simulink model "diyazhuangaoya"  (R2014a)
settings: Solver=ode45  SolverMode=SingleTasking  StartTime=0.0  StopTime=0.025  RelTol=1e-3
undefined symbols (not defined in the file): xiezhendiangan
libraries: powerlib x32, powerlib_meascontrol x8, simulink x4

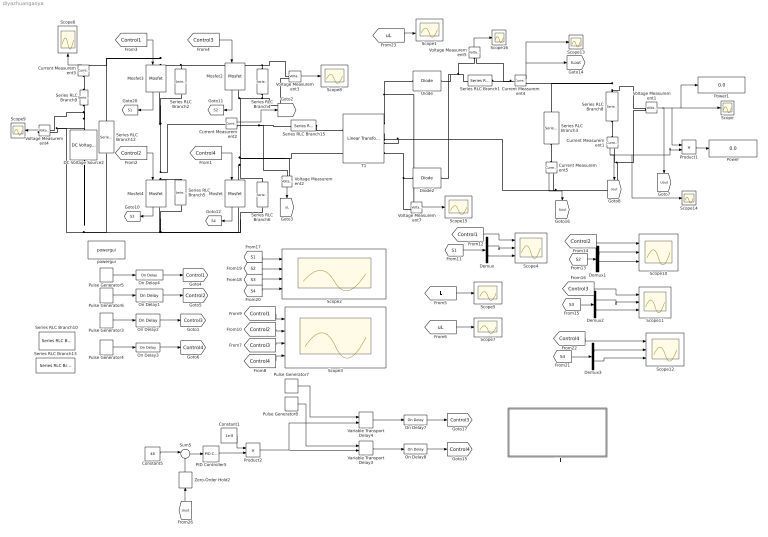
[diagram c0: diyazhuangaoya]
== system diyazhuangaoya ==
  Constant1 : Constant  Value=1e-8
  Constant5 : Constant  Value=48
  Current Measurement{1..5} (5 alike) : powerlib/Measurements/Current Measurement  PhasorSimulation=off  OutputType=Complex  PSBequivalent=0
  DC Voltage Source2 : powerlib/Electrical Sources/DC Voltage Source  Amplitude=28  Measurements=None
  Demux{,1..3} (4 alike) : Demux  Outputs=2
  Diode : powerlib/Power Electronics/Diode  Ron=0.001  Lon=0  Vf=0.8  IC=0  UseSnubber=0  Rs=500  Cs=250e-9  Measurements=off
  Diode2 : powerlib/Power Electronics/Diode  Ron=0.001  Lon=0  Vf=0.8  IC=0  UseSnubber=0  Rs=500  Cs=250e-9  Measurements=off
  Mosfet{,2..4} (4 alike) : powerlib/Power Electronics/Mosfet  Ron=3.5e-3  Lon=0  Rd=0.01  Vfd=0.7  IC=0  Rs=1e5  Cs=inf  Measurements=on
  On Delay1 : powerlib_meascontrol/Logic/On Delay  DelayType=On delay  delay=120e-9  ic=0  Ts=0
  On Delay2 : powerlib_meascontrol/Logic/On Delay  Commented=on  DelayType=On delay  delay=120e-9  ic=0  Ts=0
  On Delay3 : powerlib_meascontrol/Logic/On Delay  Commented=on  DelayType=On delay  delay=120e-9  ic=0  Ts=0
  On Delay4 : powerlib_meascontrol/Logic/On Delay  DelayType=On delay  delay=120e-9  ic=0  Ts=0
  On Delay7 : powerlib_meascontrol/Logic/On Delay  DelayType=On delay  delay=1.2e-7  ic=0  Ts=0
  On Delay8 : powerlib_meascontrol/Logic/On Delay  DelayType=On delay  delay=1.2e-7  ic=0  Ts=0
  PID Controller5 : simulink/Continuous/PID Controller  Controller=PID  TimeDomain=Continuous-time  SampleTime=-1  IntegratorMethod=Forward Euler  FilterMethod=Forward Euler  Form=Parallel  UseFilter=on  ControllerParametersSource=internal  P=0.05  I=1  D=0  N=100  InitialConditionSource=internal  InitialConditionForIntegrator=0  InitialConditionForFilter=0  ExternalReset=none  LimitOutput=off  UpperSaturationLimit=inf  LowerSaturationLimit=-inf  LinearizeAsGain=on  AntiWindupMode=none  Kb=1  TrackingMode=off  Kt=1  PParamMin=[]  PParamMax=[]  IParamMin=[]  IParamMax=[]  DParamMin=[]  DParamMax=[]  NParamMin=[]  NParamMax=[]  KbParamMin=[]  KbParamMax=[]  KtParamMin=[]  KtParamMax=[]  POutMin=[]  POutMax=[]  IOutMin=[]  IOutMax=[]  DOutMin=[]  DOutMax=[]  NOutMin=[]  NOutMax=[]  KbOutMin=[]  KbOutMax=[]  KtOutMin=[]  KtOutMax=[]  IntegratorOutMin=[]  IntegratorOutMax=[]  FilterOutMin=[]  FilterOutMax=[]  SumOutMin=[]  SumOutMax=[]  SumI1OutMin=[]  SumI1OutMax=[]  SumI2OutMin=[]  SumI2OutMax=[]  SumI3OutMin=[]  SumI3OutMax=[]  SumDOutMin=[]  SumDOutMax=[]  SaturationOutMin=[]  SaturationOutMax=[]  IntegratorContinuousStateAttributes=''  IntegratorStateMustResolveToSignalObject=off  IntegratorRTWStateStorageClass=Auto  FilterContinuousStateAttributes=''  FilterStateMustResolveToSignalObject=off  FilterRTWStateStorageClass=Auto  DifferentiatorICPrevScaledInput=0  DifferentiatorOutMin=[]  DifferentiatorOutMax=[]
  Power : Display
  Power1 : Display
  Product1 : Product
  Product2 : Product
  Pulse Generator3 : DiscretePulseGenerator  Commented=on  PulseType=Time based  Period=0.00001  PulseWidth=50  PhaseDelay=0.5*0.00001
  Pulse Generator4 : DiscretePulseGenerator  Commented=on  PulseType=Time based  Period=0.00001  PulseWidth=50  PhaseDelay=0.00001/2+0.5*0.00001
  Pulse Generator5 : DiscretePulseGenerator  PulseType=Time based  Period=0.00001  PulseWidth=50
  Pulse Generator6 : DiscretePulseGenerator  PulseType=Time based  Period=0.00001  PulseWidth=50  PhaseDelay=0.00001/2
  Pulse Generator7 : DiscretePulseGenerator  PulseType=Time based  Period=0.00001  PulseWidth=50  PhaseDelay=0.5*0.00001
  Pulse Generator8 : DiscretePulseGenerator  PulseType=Time based  Period=0.00001  PulseWidth=50  PhaseDelay=0.00001/2+0.5*0.00001
  Scope{,5..9,13..16} (10 alike) : Scope
  Scope1 : Scope  NumInputPorts=2
  Scope{4,10..12} (4 alike) : Scope  NumInputPorts=3
  Scope2 : Scope  NumInputPorts=4
  Scope3 : Scope  NumInputPorts=4
  Series RLC Branch1 : powerlib/Elements/Series RLC Branch  LConnTagsString=__new0  RConnTagsString=__new0  BranchType=RL  Resistance=0.0001  Inductance=100e-6  SetiL0=off  InitialCurrent=0  Capacitance=1e-6  Setx0=off  InitialVoltage=0  Measurements=None
  Series RLC Branch10 : powerlib/Elements/Series RLC Branch  LConnTagsString=__new0  RConnTagsString=__new0  BranchType=C  Resistance=0.0001  Inductance=2e-3  SetiL0=off  InitialCurrent=0  Capacitance=0.249e-6  Setx0=off  InitialVoltage=0  Measurements=None
  Series RLC Branch12 : powerlib/Elements/Series RLC Branch  LConnTagsString=__new0  RConnTagsString=__new0  BranchType=RC  Resistance=0.01  Inductance=2e-3  SetiL0=off  InitialCurrent=0  Capacitance=30000e-6  Setx0=off  InitialVoltage=0  Measurements=None
  Series RLC Branch13 : powerlib/Elements/Series RLC Branch  LConnTagsString=__new0  RConnTagsString=__new0  BranchType=RL  Resistance=0.0001  Inductance=10e-6  SetiL0=off  InitialCurrent=0  Capacitance=1e-6  Setx0=off  InitialVoltage=0  Measurements=None
  Series RLC Branch15 : powerlib/Elements/Series RLC Branch  LConnTagsString=__new0  RConnTagsString=__new0  BranchType=RL  Resistance=0.0001  Inductance=10e-6  SetiL0=off  InitialCurrent=0  Capacitance=1e-6  Setx0=off  InitialVoltage=0  Measurements=None
  Series RLC Branch2 : powerlib/Elements/Series RLC Branch  LConnTagsString=__new0  RConnTagsString=__new0  BranchType=C  Resistance=1  Inductance=xiezhendiangan  SetiL0=off  InitialCurrent=0  Capacitance=1020*10e-12  Setx0=off  InitialVoltage=0  Measurements=None
  Series RLC Branch3 : powerlib/Elements/Series RLC Branch  LConnTagsString=__new0  RConnTagsString=__new0  BranchType=RC  Resistance=0.01  Inductance=2e-3  SetiL0=off  InitialCurrent=0  Capacitance=200e-6  Setx0=off  InitialVoltage=0  Measurements=None
  Series RLC Branch4 : powerlib/Elements/Series RLC Branch  LConnTagsString=__new0  RConnTagsString=__new0  BranchType=C  Resistance=1  Inductance=xiezhendiangan  SetiL0=off  InitialCurrent=0  Capacitance=10e-12  Setx0=off  InitialVoltage=0  Measurements=None
  Series RLC Branch5 : powerlib/Elements/Series RLC Branch  LConnTagsString=__new0  RConnTagsString=__new0  BranchType=C  Resistance=1  Inductance=xiezhendiangan  SetiL0=off  InitialCurrent=0  Capacitance=10e-12  Setx0=off  InitialVoltage=0  Measurements=None
  Series RLC Branch6 : powerlib/Elements/Series RLC Branch  LConnTagsString=__new0  RConnTagsString=__new0  BranchType=C  Resistance=1  Inductance=xiezhendiangan  SetiL0=off  InitialCurrent=0  Capacitance=10e-12  Setx0=off  InitialVoltage=0  Measurements=None
  Series RLC Branch8 : powerlib/Elements/Series RLC Branch  LConnTagsString=__new0  RConnTagsString=__new0  BranchType=R  Resistance=1.152  Inductance=2e-3  SetiL0=off  InitialCurrent=0  Capacitance=1e-6  Setx0=off  InitialVoltage=0  Measurements=None
  Series RLC Branch9 : powerlib/Elements/Series RLC Branch  LConnTagsString=__new0  RConnTagsString=__new0  BranchType=R  Resistance=1e-2  Inductance=2e-3  SetiL0=off  InitialCurrent=0  Capacitance=1e-6  Setx0=off  InitialVoltage=0  Measurements=None
  Sum5 : Sum  Inputs=|+-
  T1 : powerlib/Elements/Linear Transformer  UNITS=SI  NominalPower=[4000 10e4]  winding1=[2 0 0]  winding2=[6 0 0]  ThreeWindings=on  winding3=[6 0 0]  RmLm=[9e+06 Inf]  Measurements=None  DataType=on
  Variable Transport Delay3 : VariableTransportDelay  VariableDelayType=Variable transport delay  MaximumDelay=0.00001*0.5  MaximumPoints=5120
  Variable Transport Delay4 : VariableTransportDelay  VariableDelayType=Variable transport delay  MaximumDelay=0.00001*0.5  MaximumPoints=5120
  Voltage Measurement{1..5,7} (6 alike) : powerlib/Measurements/Voltage Measurement  PhasorSimulation=off  OutputType=Complex  PSBequivalent=0
  Zero-Order Hold2 : ZeroOrderHold  SampleTime=1e-6
  powergui : powerlib/powergui  Priority=1  SimulationMode=Discrete  SampleTime=5e-8  frequency=60  Iterations=50  frequencyindice=0  Pbase=100e6  ErrMax=1e-4  UnitsV=kV  UnitsW=MW  buscounter=0  FunctionMessages=off  echomessages=off  EnableUseOfTLC=off  CurrentSourceSwitches=off  DisableSnubberDevices=off  DisableRonSwitches=off  DisableVfSwitches=off  DisplayEquations=off  SolverType=Tustin/Backward Euler (TBE)  Interpol=off  ExternalGateDelay=off  methode=off  Ts=100  x0status=blocks  SPID=on  SwTol=0  HookPort=off  RestoreLinks=warning  ResistiveCurrentMeasurement=off  Frange=[0:2:500]  Ylog=off  Xlog=on  ShowGrid=off  save=off  variable=ZData  structure=0  ZoomFFT=off  StartTime=0.0  cycles=1  DisplayStyle=1  fundamental=60  FreqAxis=off  MaxFrequency=1000  frequencyindicesteady=1  RmsSteady=1  display=off
  双闭环 : Subsystem  Commented=on
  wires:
  Demux1/2 -> Scope10/3
  [Control1] -> Mosfet3/1
  Product1/1 -> Power/1
  [Control4] -> Mosfet/1
  Voltage Measurement4/1 -> Scope9/1
  Product2/1 -> Variable Transport Delay4/2, Variable Transport Delay3/2
  [S2] -> Scope2/2
  [Uout] -> Zero-Order Hold2/1
  Voltage Measurement5/1 -> Scope16/1
  Constant5/1 -> Sum5/1
  Pulse Generator6/1 -> On Delay1/1
  [S4] -> Scope2/4
  Voltage Measurement1/1 -> [Uout], Power1/1, Scope/1, Product1/1
  [S2] -> Demux1/1
  Pulse Generator8/1 -> Variable Transport Delay3/1
  [Control2] -> Scope10/1
  On Delay8/1 -> [Control4]
  [uL] -> Scope7/1
  Sum5/1 -> PID Controller5/1
  On Delay1/1 -> [Control2]
  Variable Transport Delay3/1 -> On Delay8/1
  [S3] -> Demux2/1
  On Delay2/1 -> [Control3]
  Demux1/1 -> Scope10/2
  Demux2/1 -> Scope11/2
  Voltage Measurement7/1 -> Scope15/1
  On Delay7/1 -> [Control3]
  Pulse Generator4/1 -> On Delay3/1
  Variable Transport Delay4/1 -> On Delay7/1
  Current Measurement1/1 -> Product1/2, Scope14/1, [Iout]
  [Control3] -> Mosfet2/1
  Constant1/1 -> Product2/1
  Demux2/2 -> Scope11/3
  Pulse Generator7/1 -> Variable Transport Delay4/1
  Pulse Generator3/1 -> On Delay2/1
  Current Measurement5/1 -> [ILout]
  Current Measurement2/1 -> [iL]
  [S4] -> Demux3/1
  [Control2] -> Mosfet4/1
  On Delay3/1 -> [Control4]
  PID Controller5/1 -> Product2/2
  Demux3/2 -> Scope12/3
  [uL] -> Scope1/2
  [Control1] -> Scope3/1
  Pulse Generator5/1 -> On Delay4/1
  On Delay4/1 -> [Control1]
  Current Measurement3/1 -> Scope6/1
  [Control2] -> Scope3/2
  Demux/2 -> Scope4/3
  Mosfet4/1 -> [S3]
  [S1] -> Demux/1
  Voltage Measurement3/1 -> Scope8/1
  Mosfet3/1 -> [S1]
  Mosfet/1 -> [S4]
  [Control3] -> Scope3/3
  Demux3/1 -> Scope12/2
  [Control4] -> Scope12/1
  Current Measurement4/1 -> [ILout], Scope13/1
  [iL] -> Scope5/1
  [Control1] -> Scope4/1
  [Control4] -> Scope3/4
  [S3] -> Scope2/3
  [S1] -> Scope2/1
  Voltage Measurement2/1 -> [uL]
  Mosfet2/1 -> [S2]
  Demux/1 -> Scope4/2
  [Control3] -> Scope11/1
  Zero-Order Hold2/1 -> Sum5/2
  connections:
  Series RLC Branch4/RConn1 -- Series RLC Branch12/LConn1 -- Current Measurement3/RConn1 -- Mosfet3/LConn1 -- Series RLC Branch2/RConn1 -- Mosfet2/LConn1 -- Voltage Measurement3/LConn1
  Series RLC Branch5/RConn1 -- Mosfet4/LConn1 -- Current Measurement2/LConn1 -- Series RLC Branch2/LConn1 -- Mosfet3/RConn1
  T1/RConn1 -- Diode/LConn1 -- Voltage Measurement7/LConn1
  Voltage Measurement1/LConn2 -- T1/RConn2 -- T1/RConn3 -- Current Measurement5/RConn1 -- Current Measurement1/RConn1
  Diode2/LConn1 -- T1/RConn4 -- Voltage Measurement7/LConn2
  Voltage Measurement5/LConn1 -- Diode2/RConn1 -- Diode/RConn1 -- Series RLC Branch1/RConn1
  Voltage Measurement4/LConn2 -- DC Voltage Source2/LConn1 -- Series RLC Branch12/RConn1 -- Series RLC Branch5/LConn1 -- Mosfet4/RConn1 -- Mosfet/RConn1 -- Series RLC Branch6/LConn1
  Series RLC Branch8/LConn1 -- Series RLC Branch3/LConn1 -- Current Measurement4/RConn1 -- Voltage Measurement1/LConn1
  Current Measurement4/LConn1 -- Series RLC Branch1/LConn1 -- Voltage Measurement5/LConn2
  Series RLC Branch9/RConn1 -- DC Voltage Source2/RConn1 -- Voltage Measurement4/LConn1
  Current Measurement1/LConn1 -- Series RLC Branch8/RConn1
  Current Measurement3/LConn1 -- Series RLC Branch9/LConn1
  Current Measurement5/LConn1 -- Series RLC Branch3/RConn1
  Current Measurement2/RConn1 -- Series RLC Branch15/RConn1 -- Voltage Measurement2/LConn1
  Series RLC Branch15/LConn1 -- T1/LConn1
  Series RLC Branch4/LConn1 -- Voltage Measurement3/LConn2 -- Mosfet2/RConn1 -- T1/LConn2 -- Voltage Measurement2/LConn2 -- Mosfet/LConn1 -- Series RLC Branch6/RConn1

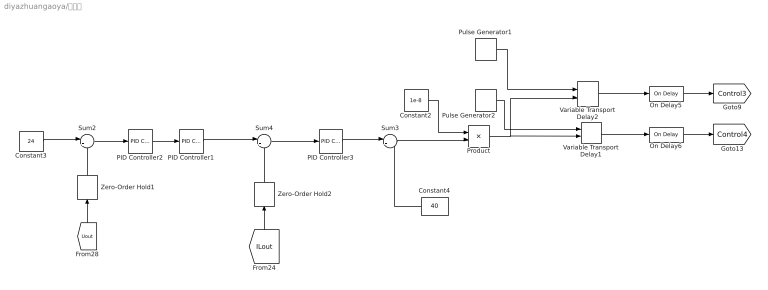
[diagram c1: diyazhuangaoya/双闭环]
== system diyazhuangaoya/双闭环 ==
  Constant2 : Constant  Value=1e-8
  Constant3 : Constant  Value=24
  Constant4 : Constant  Value=40
  On Delay5 : powerlib_meascontrol/Logic/On Delay  DelayType=On delay  delay=1.2e-7  ic=0  Ts=0
  On Delay6 : powerlib_meascontrol/Logic/On Delay  DelayType=On delay  delay=1.2e-7  ic=0  Ts=0
  PID Controller1 : simulink/Continuous/PID Controller  Controller=PID  TimeDomain=Continuous-time  SampleTime=-1  IntegratorMethod=Forward Euler  FilterMethod=Forward Euler  Form=Parallel  UseFilter=on  ControllerParametersSource=internal  P=0.05  I=1  D=0  N=100  InitialConditionSource=internal  InitialConditionForIntegrator=0  InitialConditionForFilter=0  ExternalReset=none  LimitOutput=off  UpperSaturationLimit=inf  LowerSaturationLimit=-inf  LinearizeAsGain=on  AntiWindupMode=none  Kb=1  TrackingMode=off  Kt=1  PParamMin=[]  PParamMax=[]  IParamMin=[]  IParamMax=[]  DParamMin=[]  DParamMax=[]  NParamMin=[]  NParamMax=[]  KbParamMin=[]  KbParamMax=[]  KtParamMin=[]  KtParamMax=[]  POutMin=[]  POutMax=[]  IOutMin=[]  IOutMax=[]  DOutMin=[]  DOutMax=[]  NOutMin=[]  NOutMax=[]  KbOutMin=[]  KbOutMax=[]  KtOutMin=[]  KtOutMax=[]  IntegratorOutMin=[]  IntegratorOutMax=[]  FilterOutMin=[]  FilterOutMax=[]  SumOutMin=[]  SumOutMax=[]  SumI1OutMin=[]  SumI1OutMax=[]  SumI2OutMin=[]  SumI2OutMax=[]  SumI3OutMin=[]  SumI3OutMax=[]  SumDOutMin=[]  SumDOutMax=[]  SaturationOutMin=[]  SaturationOutMax=[]  IntegratorContinuousStateAttributes=''  IntegratorStateMustResolveToSignalObject=off  IntegratorRTWStateStorageClass=Auto  FilterContinuousStateAttributes=''  FilterStateMustResolveToSignalObject=off  FilterRTWStateStorageClass=Auto  DifferentiatorICPrevScaledInput=0  DifferentiatorOutMin=[]  DifferentiatorOutMax=[]
  PID Controller2 : simulink/Continuous/PID Controller  Controller=PID  TimeDomain=Continuous-time  SampleTime=-1  IntegratorMethod=Forward Euler  FilterMethod=Forward Euler  Form=Parallel  UseFilter=on  ControllerParametersSource=internal  P=0.05  I=1  D=0  N=100  InitialConditionSource=internal  InitialConditionForIntegrator=0  InitialConditionForFilter=0  ExternalReset=none  LimitOutput=off  UpperSaturationLimit=inf  LowerSaturationLimit=-inf  LinearizeAsGain=on  AntiWindupMode=none  Kb=1  TrackingMode=off  Kt=1  PParamMin=[]  PParamMax=[]  IParamMin=[]  IParamMax=[]  DParamMin=[]  DParamMax=[]  NParamMin=[]  NParamMax=[]  KbParamMin=[]  KbParamMax=[]  KtParamMin=[]  KtParamMax=[]  POutMin=[]  POutMax=[]  IOutMin=[]  IOutMax=[]  DOutMin=[]  DOutMax=[]  NOutMin=[]  NOutMax=[]  KbOutMin=[]  KbOutMax=[]  KtOutMin=[]  KtOutMax=[]  IntegratorOutMin=[]  IntegratorOutMax=[]  FilterOutMin=[]  FilterOutMax=[]  SumOutMin=[]  SumOutMax=[]  SumI1OutMin=[]  SumI1OutMax=[]  SumI2OutMin=[]  SumI2OutMax=[]  SumI3OutMin=[]  SumI3OutMax=[]  SumDOutMin=[]  SumDOutMax=[]  SaturationOutMin=[]  SaturationOutMax=[]  IntegratorContinuousStateAttributes=''  IntegratorStateMustResolveToSignalObject=off  IntegratorRTWStateStorageClass=Auto  FilterContinuousStateAttributes=''  FilterStateMustResolveToSignalObject=off  FilterRTWStateStorageClass=Auto  DifferentiatorICPrevScaledInput=0  DifferentiatorOutMin=[]  DifferentiatorOutMax=[]
  PID Controller3 : simulink/Continuous/PID Controller  Controller=PID  TimeDomain=Continuous-time  SampleTime=-1  IntegratorMethod=Forward Euler  FilterMethod=Forward Euler  Form=Parallel  UseFilter=on  ControllerParametersSource=internal  P=2  I=0.1  D=0  N=100  InitialConditionSource=internal  InitialConditionForIntegrator=0  InitialConditionForFilter=0  ExternalReset=none  LimitOutput=off  UpperSaturationLimit=inf  LowerSaturationLimit=-inf  LinearizeAsGain=on  AntiWindupMode=none  Kb=1  TrackingMode=off  Kt=1  PParamMin=[]  PParamMax=[]  IParamMin=[]  IParamMax=[]  DParamMin=[]  DParamMax=[]  NParamMin=[]  NParamMax=[]  KbParamMin=[]  KbParamMax=[]  KtParamMin=[]  KtParamMax=[]  POutMin=[]  POutMax=[]  IOutMin=[]  IOutMax=[]  DOutMin=[]  DOutMax=[]  NOutMin=[]  NOutMax=[]  KbOutMin=[]  KbOutMax=[]  KtOutMin=[]  KtOutMax=[]  IntegratorOutMin=[]  IntegratorOutMax=[]  FilterOutMin=[]  FilterOutMax=[]  SumOutMin=[]  SumOutMax=[]  SumI1OutMin=[]  SumI1OutMax=[]  SumI2OutMin=[]  SumI2OutMax=[]  SumI3OutMin=[]  SumI3OutMax=[]  SumDOutMin=[]  SumDOutMax=[]  SaturationOutMin=[]  SaturationOutMax=[]  IntegratorContinuousStateAttributes=''  IntegratorStateMustResolveToSignalObject=off  IntegratorRTWStateStorageClass=Auto  FilterContinuousStateAttributes=''  FilterStateMustResolveToSignalObject=off  FilterRTWStateStorageClass=Auto  DifferentiatorICPrevScaledInput=0  DifferentiatorOutMin=[]  DifferentiatorOutMax=[]
  Product : Product
  Pulse Generator1 : DiscretePulseGenerator  PulseType=Time based  Period=0.00001  PulseWidth=50  PhaseDelay=0.5*0.00001
  Pulse Generator2 : DiscretePulseGenerator  PulseType=Time based  Period=0.00001  PulseWidth=50  PhaseDelay=0.00001/2+0.5*0.00001
  Sum2 : Sum  Inputs=|+-
  Sum3 : Sum  Inputs=|-+
  Sum4 : Sum  Inputs=|+-
  Variable Transport Delay1 : VariableTransportDelay  VariableDelayType=Variable transport delay  MaximumDelay=0.00001*0.5  MaximumPoints=5120
  Variable Transport Delay2 : VariableTransportDelay  VariableDelayType=Variable transport delay  MaximumDelay=0.00001*0.5  MaximumPoints=5120
  Zero-Order Hold1 : ZeroOrderHold  SampleTime=1e-5
  Zero-Order Hold2 : ZeroOrderHold  SampleTime=1e-5
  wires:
  On Delay5/1 -> [Control3]
  Pulse Generator1/1 -> Variable Transport Delay2/1
  Constant3/1 -> Sum2/1
  [Uout] -> Zero-Order Hold1/1
  Variable Transport Delay2/1 -> On Delay5/1
  Product/1 -> Variable Transport Delay2/2, Variable Transport Delay1/2
  On Delay6/1 -> [Control4]
  Sum2/1 -> PID Controller2/1
  Pulse Generator2/1 -> Variable Transport Delay1/1
  PID Controller3/1 -> Sum3/1
  Zero-Order Hold1/1 -> Sum2/2
  PID Controller2/1 -> PID Controller1/1
  [ILout] -> Zero-Order Hold2/1
  Sum3/1 -> Product/2
  Constant4/1 -> Sum3/2
  Constant2/1 -> Product/1
  Variable Transport Delay1/1 -> On Delay6/1
  PID Controller1/1 -> Sum4/1
  Sum4/1 -> PID Controller3/1
  Zero-Order Hold2/1 -> Sum4/2
